One B-rep face of a CAD part: STEP entity #26076.
In plain terms, the planar face has unit normal (-1, 0, 0).
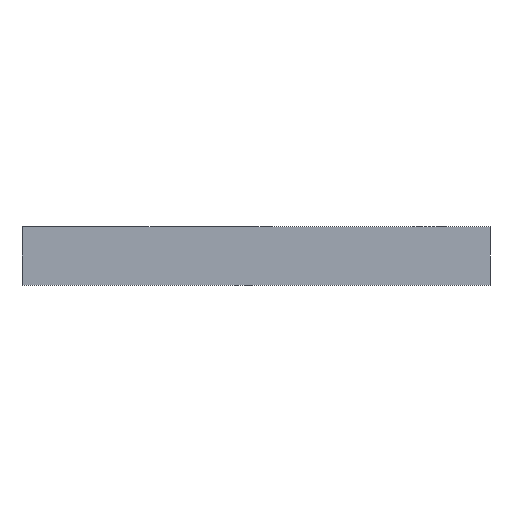
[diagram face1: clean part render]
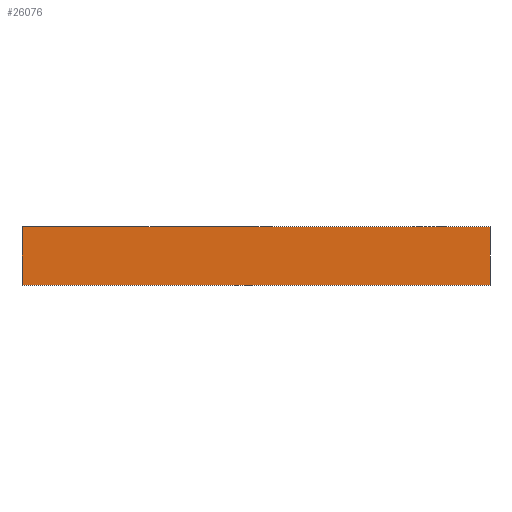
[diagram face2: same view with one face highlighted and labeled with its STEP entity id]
Its self-contained STEP definition (entity closure, numbers rounded to 3 decimals):
#26076 = ADVANCED_FACE('',(#26077),#26091,.F.);
#26077 = FACE_BOUND('',#26078,.F.);
#26078 = EDGE_LOOP('',(#26079,#26114,#26142,#26170));
#26079 = ORIENTED_EDGE('',*,*,#26080,.F.);
#26080 = EDGE_CURVE('',#26081,#26083,#26085,.T.);
#26081 = VERTEX_POINT('',#26082);
#26082 = CARTESIAN_POINT('',(0.,0.,0.));
#26083 = VERTEX_POINT('',#26084);
#26084 = CARTESIAN_POINT('',(0.,0.,1.5));
#26085 = SURFACE_CURVE('',#26086,(#26090,#26102),.PCURVE_S1.);
#26086 = LINE('',#26087,#26088);
#26087 = CARTESIAN_POINT('',(0.,0.,0.));
#26088 = VECTOR('',#26089,1.);
#26089 = DIRECTION('',(0.,0.,1.));
#26090 = PCURVE('',#26091,#26096);
#26091 = PLANE('',#26092);
#26092 = AXIS2_PLACEMENT_3D('',#26093,#26094,#26095);
#26093 = CARTESIAN_POINT('',(0.,0.,0.));
#26094 = DIRECTION('',(1.,0.,-0.));
#26095 = DIRECTION('',(0.,0.,1.));
#26096 = DEFINITIONAL_REPRESENTATION('',(#26097),#26101);
#26097 = LINE('',#26098,#26099);
#26098 = CARTESIAN_POINT('',(0.,0.));
#26099 = VECTOR('',#26100,1.);
#26100 = DIRECTION('',(1.,0.));
#26101 = ( GEOMETRIC_REPRESENTATION_CONTEXT(2) 
PARAMETRIC_REPRESENTATION_CONTEXT() REPRESENTATION_CONTEXT('2D SPACE',''
  ) );
#26102 = PCURVE('',#26103,#26108);
#26103 = PLANE('',#26104);
#26104 = AXIS2_PLACEMENT_3D('',#26105,#26106,#26107);
#26105 = CARTESIAN_POINT('',(0.,0.,0.));
#26106 = DIRECTION('',(-0.,1.,0.));
#26107 = DIRECTION('',(0.,0.,1.));
#26108 = DEFINITIONAL_REPRESENTATION('',(#26109),#26113);
#26109 = LINE('',#26110,#26111);
#26110 = CARTESIAN_POINT('',(0.,0.));
#26111 = VECTOR('',#26112,1.);
#26112 = DIRECTION('',(1.,0.));
#26113 = ( GEOMETRIC_REPRESENTATION_CONTEXT(2) 
PARAMETRIC_REPRESENTATION_CONTEXT() REPRESENTATION_CONTEXT('2D SPACE',''
  ) );
#26114 = ORIENTED_EDGE('',*,*,#26115,.T.);
#26115 = EDGE_CURVE('',#26081,#26116,#26118,.T.);
#26116 = VERTEX_POINT('',#26117);
#26117 = CARTESIAN_POINT('',(0.,12.,0.));
#26118 = SURFACE_CURVE('',#26119,(#26123,#26130),.PCURVE_S1.);
#26119 = LINE('',#26120,#26121);
#26120 = CARTESIAN_POINT('',(0.,0.,0.));
#26121 = VECTOR('',#26122,1.);
#26122 = DIRECTION('',(-0.,1.,0.));
#26123 = PCURVE('',#26091,#26124);
#26124 = DEFINITIONAL_REPRESENTATION('',(#26125),#26129);
#26125 = LINE('',#26126,#26127);
#26126 = CARTESIAN_POINT('',(0.,0.));
#26127 = VECTOR('',#26128,1.);
#26128 = DIRECTION('',(0.,-1.));
#26129 = ( GEOMETRIC_REPRESENTATION_CONTEXT(2) 
PARAMETRIC_REPRESENTATION_CONTEXT() REPRESENTATION_CONTEXT('2D SPACE',''
  ) );
#26130 = PCURVE('',#26131,#26136);
#26131 = PLANE('',#26132);
#26132 = AXIS2_PLACEMENT_3D('',#26133,#26134,#26135);
#26133 = CARTESIAN_POINT('',(0.,0.,0.));
#26134 = DIRECTION('',(0.,0.,1.));
#26135 = DIRECTION('',(1.,0.,-0.));
#26136 = DEFINITIONAL_REPRESENTATION('',(#26137),#26141);
#26137 = LINE('',#26138,#26139);
#26138 = CARTESIAN_POINT('',(0.,0.));
#26139 = VECTOR('',#26140,1.);
#26140 = DIRECTION('',(0.,1.));
#26141 = ( GEOMETRIC_REPRESENTATION_CONTEXT(2) 
PARAMETRIC_REPRESENTATION_CONTEXT() REPRESENTATION_CONTEXT('2D SPACE',''
  ) );
#26142 = ORIENTED_EDGE('',*,*,#26143,.T.);
#26143 = EDGE_CURVE('',#26116,#26144,#26146,.T.);
#26144 = VERTEX_POINT('',#26145);
#26145 = CARTESIAN_POINT('',(0.,12.,1.5));
#26146 = SURFACE_CURVE('',#26147,(#26151,#26158),.PCURVE_S1.);
#26147 = LINE('',#26148,#26149);
#26148 = CARTESIAN_POINT('',(0.,12.,0.));
#26149 = VECTOR('',#26150,1.);
#26150 = DIRECTION('',(0.,0.,1.));
#26151 = PCURVE('',#26091,#26152);
#26152 = DEFINITIONAL_REPRESENTATION('',(#26153),#26157);
#26153 = LINE('',#26154,#26155);
#26154 = CARTESIAN_POINT('',(0.,-12.));
#26155 = VECTOR('',#26156,1.);
#26156 = DIRECTION('',(1.,0.));
#26157 = ( GEOMETRIC_REPRESENTATION_CONTEXT(2) 
PARAMETRIC_REPRESENTATION_CONTEXT() REPRESENTATION_CONTEXT('2D SPACE',''
  ) );
#26158 = PCURVE('',#26159,#26164);
#26159 = PLANE('',#26160);
#26160 = AXIS2_PLACEMENT_3D('',#26161,#26162,#26163);
#26161 = CARTESIAN_POINT('',(0.,12.,0.));
#26162 = DIRECTION('',(-0.,1.,0.));
#26163 = DIRECTION('',(0.,0.,1.));
#26164 = DEFINITIONAL_REPRESENTATION('',(#26165),#26169);
#26165 = LINE('',#26166,#26167);
#26166 = CARTESIAN_POINT('',(0.,0.));
#26167 = VECTOR('',#26168,1.);
#26168 = DIRECTION('',(1.,0.));
#26169 = ( GEOMETRIC_REPRESENTATION_CONTEXT(2) 
PARAMETRIC_REPRESENTATION_CONTEXT() REPRESENTATION_CONTEXT('2D SPACE',''
  ) );
#26170 = ORIENTED_EDGE('',*,*,#26171,.F.);
#26171 = EDGE_CURVE('',#26083,#26144,#26172,.T.);
#26172 = SURFACE_CURVE('',#26173,(#26177,#26184),.PCURVE_S1.);
#26173 = LINE('',#26174,#26175);
#26174 = CARTESIAN_POINT('',(0.,0.,1.5));
#26175 = VECTOR('',#26176,1.);
#26176 = DIRECTION('',(-0.,1.,0.));
#26177 = PCURVE('',#26091,#26178);
#26178 = DEFINITIONAL_REPRESENTATION('',(#26179),#26183);
#26179 = LINE('',#26180,#26181);
#26180 = CARTESIAN_POINT('',(1.5,0.));
#26181 = VECTOR('',#26182,1.);
#26182 = DIRECTION('',(0.,-1.));
#26183 = ( GEOMETRIC_REPRESENTATION_CONTEXT(2) 
PARAMETRIC_REPRESENTATION_CONTEXT() REPRESENTATION_CONTEXT('2D SPACE',''
  ) );
#26184 = PCURVE('',#26185,#26190);
#26185 = PLANE('',#26186);
#26186 = AXIS2_PLACEMENT_3D('',#26187,#26188,#26189);
#26187 = CARTESIAN_POINT('',(0.,0.,1.5));
#26188 = DIRECTION('',(0.,0.,1.));
#26189 = DIRECTION('',(1.,0.,-0.));
#26190 = DEFINITIONAL_REPRESENTATION('',(#26191),#26195);
#26191 = LINE('',#26192,#26193);
#26192 = CARTESIAN_POINT('',(0.,0.));
#26193 = VECTOR('',#26194,1.);
#26194 = DIRECTION('',(0.,1.));
#26195 = ( GEOMETRIC_REPRESENTATION_CONTEXT(2) 
PARAMETRIC_REPRESENTATION_CONTEXT() REPRESENTATION_CONTEXT('2D SPACE',''
  ) );
